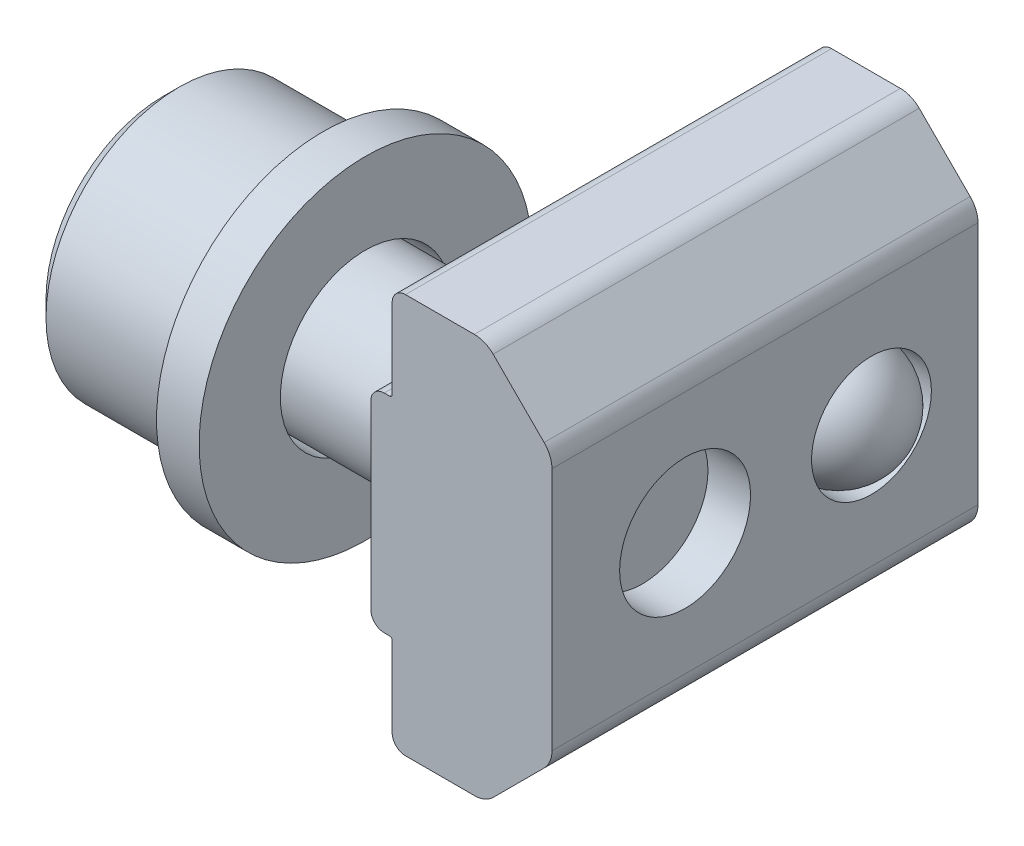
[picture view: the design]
ISO-10303-21;
HEADER;
FILE_DESCRIPTION(('STEP AP214'),'2;1');
FILE_NAME('part.step','',(''),(''),'','','');
FILE_SCHEMA(('AUTOMOTIVE_DESIGN { 1 0 10303 214 1 1 1 1 }'));
ENDSEC;
DATA;
#1=APPLICATION_CONTEXT('core data for automotive mechanical design processes');
#2=APPLICATION_PROTOCOL_DEFINITION('international standard','automotive_design',2000,#1);
#3=PRODUCT_CONTEXT('',#1,'mechanical');
#4=PRODUCT('Part','Part','',(#3));
#5=PRODUCT_RELATED_PRODUCT_CATEGORY('part','',(#4));
#6=PRODUCT_DEFINITION_FORMATION('','',#4);
#7=PRODUCT_DEFINITION_CONTEXT('part definition',#1,'design');
#8=PRODUCT_DEFINITION('design','',#6,#7);
#9=PRODUCT_DEFINITION_SHAPE('','',#8);
#10=(LENGTH_UNIT() NAMED_UNIT(*) SI_UNIT(.MILLI.,.METRE.));
#11=(NAMED_UNIT(*) PLANE_ANGLE_UNIT() SI_UNIT($,.RADIAN.));
#12=(NAMED_UNIT(*) SI_UNIT($,.STERADIAN.) SOLID_ANGLE_UNIT());
#13=UNCERTAINTY_MEASURE_WITH_UNIT(LENGTH_MEASURE(1.E-05),#10,'distance_accuracy_value','');
#14=(GEOMETRIC_REPRESENTATION_CONTEXT(3) GLOBAL_UNCERTAINTY_ASSIGNED_CONTEXT((#13)) GLOBAL_UNIT_ASSIGNED_CONTEXT((#10,
#11,#12)) REPRESENTATION_CONTEXT('',''));
#15=CARTESIAN_POINT('',(0.,0.,0.));
#16=DIRECTION('',(0.,0.,1.));
#17=DIRECTION('',(1.,0.,0.));
#18=AXIS2_PLACEMENT_3D('',#15,#16,#17);
#19=CARTESIAN_POINT('',(11.,4.5857864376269,-11.));
#20=DIRECTION('',(0.,0.,1.));
#21=DIRECTION('',(1.,0.,0.));
#22=AXIS2_PLACEMENT_3D('',#19,#20,#21);
#23=CYLINDRICAL_SURFACE('',#22,0.999999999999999);
#24=CARTESIAN_POINT('',(11.,4.5857864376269,5.));
#25=DIRECTION('',(0.,0.,1.));
#26=DIRECTION('',(1.,0.,0.));
#27=AXIS2_PLACEMENT_3D('',#24,#25,#26);
#28=CIRCLE('',#27,0.999999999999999);
#29=CARTESIAN_POINT('',(12.,4.5857864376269,5.));
#30=VERTEX_POINT('',#29);
#31=CARTESIAN_POINT('',(11.7071067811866,5.29289321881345,5.));
#32=VERTEX_POINT('',#31);
#33=EDGE_CURVE('E215',#30,#32,#28,.T.);
#34=ORIENTED_EDGE('',*,*,#33,.F.);
#35=DIRECTION('',(0.,0.,1.));
#36=VECTOR('',#35,1.);
#37=CARTESIAN_POINT('',(12.,4.5857864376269,-11.));
#38=LINE('',#37,#36);
#39=CARTESIAN_POINT('',(12.,4.5857864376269,-11.));
#40=VERTEX_POINT('',#39);
#41=EDGE_CURVE('E12',#40,#30,#38,.T.);
#42=ORIENTED_EDGE('',*,*,#41,.F.);
#43=CARTESIAN_POINT('',(11.,4.5857864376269,-11.));
#44=DIRECTION('',(0.,0.,1.));
#45=DIRECTION('',(1.,0.,0.));
#46=AXIS2_PLACEMENT_3D('',#43,#44,#45);
#47=CIRCLE('',#46,0.999999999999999);
#48=CARTESIAN_POINT('',(11.7071067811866,5.29289321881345,-11.));
#49=VERTEX_POINT('',#48);
#50=EDGE_CURVE('E272',#40,#49,#47,.T.);
#51=ORIENTED_EDGE('',*,*,#50,.T.);
#52=DIRECTION('',(0.,0.,1.));
#53=VECTOR('',#52,1.);
#54=CARTESIAN_POINT('',(11.7071067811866,5.29289321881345,-11.));
#55=LINE('',#54,#53);
#56=EDGE_CURVE('E137',#49,#32,#55,.T.);
#57=ORIENTED_EDGE('',*,*,#56,.T.);
#58=EDGE_LOOP('',(#34,#42,#51,#57));
#59=FACE_BOUND('',#58,.T.);
#60=ADVANCED_FACE('F45',(#59),#23,.T.);
#61=CARTESIAN_POINT('',(12.,-4.5857864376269,-11.));
#62=DIRECTION('',(1.,0.,0.));
#63=DIRECTION('',(0.,0.,-1.));
#64=AXIS2_PLACEMENT_3D('',#61,#62,#63);
#65=PLANE('',#64);
#66=CARTESIAN_POINT('',(12.,0.,0.));
#67=DIRECTION('',(1.,0.,0.));
#68=DIRECTION('',(0.,0.,-1.));
#69=AXIS2_PLACEMENT_3D('',#66,#67,#68);
#70=CIRCLE('',#69,2.4585);
#71=CARTESIAN_POINT('',(12.,0.,-2.4585));
#72=VERTEX_POINT('',#71);
#73=EDGE_CURVE('E48',#72,#72,#70,.T.);
#74=ORIENTED_EDGE('',*,*,#73,.F.);
#75=EDGE_LOOP('',(#74));
#76=FACE_BOUND('',#75,.T.);
#77=CARTESIAN_POINT('',(12.,0.,-7.));
#78=DIRECTION('',(1.,0.,0.));
#79=DIRECTION('',(0.,0.,-1.));
#80=AXIS2_PLACEMENT_3D('',#77,#78,#79);
#81=CIRCLE('',#80,2.25);
#82=CARTESIAN_POINT('',(12.,0.,-9.25));
#83=VERTEX_POINT('',#82);
#84=EDGE_CURVE('E219',#83,#83,#81,.T.);
#85=ORIENTED_EDGE('',*,*,#84,.F.);
#86=EDGE_LOOP('',(#85));
#87=FACE_BOUND('',#86,.T.);
#88=DIRECTION('',(0.,1.,0.));
#89=VECTOR('',#88,1.);
#90=CARTESIAN_POINT('',(12.,-4.5857864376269,5.));
#91=LINE('',#90,#89);
#92=CARTESIAN_POINT('',(12.,-4.5857864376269,5.));
#93=VERTEX_POINT('',#92);
#94=EDGE_CURVE('E270',#93,#30,#91,.T.);
#95=ORIENTED_EDGE('',*,*,#94,.F.);
#96=DIRECTION('',(0.,0.,1.));
#97=VECTOR('',#96,1.);
#98=CARTESIAN_POINT('',(12.,-4.5857864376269,-11.));
#99=LINE('',#98,#97);
#100=CARTESIAN_POINT('',(12.,-4.5857864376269,-11.));
#101=VERTEX_POINT('',#100);
#102=EDGE_CURVE('E54',#101,#93,#99,.T.);
#103=ORIENTED_EDGE('',*,*,#102,.F.);
#104=DIRECTION('',(0.,1.,0.));
#105=VECTOR('',#104,1.);
#106=CARTESIAN_POINT('',(12.,-4.5857864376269,-11.));
#107=LINE('',#106,#105);
#108=EDGE_CURVE('E205',#101,#40,#107,.T.);
#109=ORIENTED_EDGE('',*,*,#108,.T.);
#110=ORIENTED_EDGE('',*,*,#41,.T.);
#111=EDGE_LOOP('',(#95,#103,#109,#110));
#112=FACE_BOUND('',#111,.T.);
#113=ADVANCED_FACE('F309',(#76,#87,#112),#65,.T.);
#114=CARTESIAN_POINT('',(11.,-4.5857864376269,-11.));
#115=DIRECTION('',(0.,0.,1.));
#116=DIRECTION('',(1.,0.,0.));
#117=AXIS2_PLACEMENT_3D('',#114,#115,#116);
#118=CYLINDRICAL_SURFACE('',#117,0.999999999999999);
#119=CARTESIAN_POINT('',(11.,-4.5857864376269,5.));
#120=DIRECTION('',(0.,0.,1.));
#121=DIRECTION('',(1.,0.,0.));
#122=AXIS2_PLACEMENT_3D('',#119,#120,#121);
#123=CIRCLE('',#122,0.999999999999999);
#124=CARTESIAN_POINT('',(11.7071067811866,-5.29289321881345,5.));
#125=VERTEX_POINT('',#124);
#126=EDGE_CURVE('E192',#125,#93,#123,.T.);
#127=ORIENTED_EDGE('',*,*,#126,.F.);
#128=DIRECTION('',(0.,0.,1.));
#129=VECTOR('',#128,1.);
#130=CARTESIAN_POINT('',(11.7071067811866,-5.29289321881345,-11.));
#131=LINE('',#130,#129);
#132=CARTESIAN_POINT('',(11.7071067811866,-5.29289321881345,-11.));
#133=VERTEX_POINT('',#132);
#134=EDGE_CURVE('E187',#133,#125,#131,.T.);
#135=ORIENTED_EDGE('',*,*,#134,.F.);
#136=CARTESIAN_POINT('',(11.,-4.5857864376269,-11.));
#137=DIRECTION('',(0.,0.,1.));
#138=DIRECTION('',(1.,0.,0.));
#139=AXIS2_PLACEMENT_3D('',#136,#137,#138);
#140=CIRCLE('',#139,0.999999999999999);
#141=EDGE_CURVE('E190',#133,#101,#140,.T.);
#142=ORIENTED_EDGE('',*,*,#141,.T.);
#143=ORIENTED_EDGE('',*,*,#102,.T.);
#144=EDGE_LOOP('',(#127,#135,#142,#143));
#145=FACE_BOUND('',#144,.T.);
#146=ADVANCED_FACE('F189',(#145),#118,.T.);
#147=CARTESIAN_POINT('',(9.79289321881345,-7.20710678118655,-11.));
#148=DIRECTION('',(0.707106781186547,-0.707106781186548,0.));
#149=DIRECTION('',(0.707106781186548,0.707106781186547,0.));
#150=AXIS2_PLACEMENT_3D('',#147,#148,#149);
#151=PLANE('',#150);
#152=DIRECTION('',(0.707106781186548,0.707106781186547,0.));
#153=VECTOR('',#152,1.);
#154=CARTESIAN_POINT('',(9.79289321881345,-7.20710678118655,5.));
#155=LINE('',#154,#153);
#156=CARTESIAN_POINT('',(9.79289321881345,-7.20710678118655,5.));
#157=VERTEX_POINT('',#156);
#158=EDGE_CURVE('E267',#157,#125,#155,.T.);
#159=ORIENTED_EDGE('',*,*,#158,.F.);
#160=DIRECTION('',(0.,0.,1.));
#161=VECTOR('',#160,1.);
#162=CARTESIAN_POINT('',(9.79289321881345,-7.20710678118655,-11.));
#163=LINE('',#162,#161);
#164=CARTESIAN_POINT('',(9.79289321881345,-7.20710678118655,-11.));
#165=VERTEX_POINT('',#164);
#166=EDGE_CURVE('E197',#165,#157,#163,.T.);
#167=ORIENTED_EDGE('',*,*,#166,.F.);
#168=DIRECTION('',(0.707106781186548,0.707106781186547,0.));
#169=VECTOR('',#168,1.);
#170=CARTESIAN_POINT('',(9.79289321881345,-7.20710678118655,-11.));
#171=LINE('',#170,#169);
#172=EDGE_CURVE('E203',#165,#133,#171,.T.);
#173=ORIENTED_EDGE('',*,*,#172,.T.);
#174=ORIENTED_EDGE('',*,*,#134,.T.);
#175=EDGE_LOOP('',(#159,#167,#173,#174));
#176=FACE_BOUND('',#175,.T.);
#177=ADVANCED_FACE('F207',(#176),#151,.T.);
#178=CARTESIAN_POINT('',(9.08578643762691,-6.5,-11.));
#179=DIRECTION('',(0.,0.,1.));
#180=DIRECTION('',(1.,0.,0.));
#181=AXIS2_PLACEMENT_3D('',#178,#179,#180);
#182=CYLINDRICAL_SURFACE('',#181,1.);
#183=CARTESIAN_POINT('',(9.08578643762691,-6.5,5.));
#184=DIRECTION('',(0.,0.,1.));
#185=DIRECTION('',(1.,0.,0.));
#186=AXIS2_PLACEMENT_3D('',#183,#184,#185);
#187=CIRCLE('',#186,1.);
#188=CARTESIAN_POINT('',(9.08578643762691,-7.5,5.));
#189=VERTEX_POINT('',#188);
#190=EDGE_CURVE('E264',#189,#157,#187,.T.);
#191=ORIENTED_EDGE('',*,*,#190,.F.);
#192=DIRECTION('',(0.,0.,1.));
#193=VECTOR('',#192,1.);
#194=CARTESIAN_POINT('',(9.08578643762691,-7.5,-11.));
#195=LINE('',#194,#193);
#196=CARTESIAN_POINT('',(9.08578643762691,-7.5,-11.));
#197=VERTEX_POINT('',#196);
#198=EDGE_CURVE('E276',#197,#189,#195,.T.);
#199=ORIENTED_EDGE('',*,*,#198,.F.);
#200=CARTESIAN_POINT('',(9.08578643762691,-6.5,-11.));
#201=DIRECTION('',(0.,0.,1.));
#202=DIRECTION('',(1.,0.,0.));
#203=AXIS2_PLACEMENT_3D('',#200,#201,#202);
#204=CIRCLE('',#203,1.);
#205=EDGE_CURVE('E208',#197,#165,#204,.T.);
#206=ORIENTED_EDGE('',*,*,#205,.T.);
#207=ORIENTED_EDGE('',*,*,#166,.T.);
#208=EDGE_LOOP('',(#191,#199,#206,#207));
#209=FACE_BOUND('',#208,.T.);
#210=ADVANCED_FACE('F325',(#209),#182,.T.);
#211=CARTESIAN_POINT('',(6.49999999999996,-7.5,-11.));
#212=DIRECTION('',(0.,-1.,0.));
#213=DIRECTION('',(0.,0.,-1.));
#214=AXIS2_PLACEMENT_3D('',#211,#212,#213);
#215=PLANE('',#214);
#216=DIRECTION('',(1.,0.,0.));
#217=VECTOR('',#216,1.);
#218=CARTESIAN_POINT('',(6.49999999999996,-7.5,5.));
#219=LINE('',#218,#217);
#220=CARTESIAN_POINT('',(6.49999999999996,-7.5,5.));
#221=VERTEX_POINT('',#220);
#222=EDGE_CURVE('E261',#221,#189,#219,.T.);
#223=ORIENTED_EDGE('',*,*,#222,.F.);
#224=DIRECTION('',(0.,0.,1.));
#225=VECTOR('',#224,1.);
#226=CARTESIAN_POINT('',(6.49999999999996,-7.5,-11.));
#227=LINE('',#226,#225);
#228=CARTESIAN_POINT('',(6.49999999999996,-7.5,-11.));
#229=VERTEX_POINT('',#228);
#230=EDGE_CURVE('E278',#229,#221,#227,.T.);
#231=ORIENTED_EDGE('',*,*,#230,.F.);
#232=DIRECTION('',(1.,0.,0.));
#233=VECTOR('',#232,1.);
#234=CARTESIAN_POINT('',(6.49999999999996,-7.5,-11.));
#235=LINE('',#234,#233);
#236=EDGE_CURVE('E210',#229,#197,#235,.T.);
#237=ORIENTED_EDGE('',*,*,#236,.T.);
#238=ORIENTED_EDGE('',*,*,#198,.T.);
#239=EDGE_LOOP('',(#223,#231,#237,#238));
#240=FACE_BOUND('',#239,.T.);
#241=ADVANCED_FACE('F328',(#240),#215,.T.);
#242=CARTESIAN_POINT('',(6.49999999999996,-7.00000000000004,-11.));
#243=DIRECTION('',(0.,0.,1.));
#244=DIRECTION('',(1.,0.,0.));
#245=AXIS2_PLACEMENT_3D('',#242,#243,#244);
#246=CYLINDRICAL_SURFACE('',#245,0.499999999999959);
#247=CARTESIAN_POINT('',(6.49999999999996,-7.00000000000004,5.));
#248=DIRECTION('',(0.,0.,1.));
#249=DIRECTION('',(1.,0.,0.));
#250=AXIS2_PLACEMENT_3D('',#247,#248,#249);
#251=CIRCLE('',#250,0.499999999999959);
#252=CARTESIAN_POINT('',(6.,-7.00000000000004,5.));
#253=VERTEX_POINT('',#252);
#254=EDGE_CURVE('E258',#253,#221,#251,.T.);
#255=ORIENTED_EDGE('',*,*,#254,.F.);
#256=DIRECTION('',(0.,0.,1.));
#257=VECTOR('',#256,1.);
#258=CARTESIAN_POINT('',(6.,-7.00000000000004,-11.));
#259=LINE('',#258,#257);
#260=CARTESIAN_POINT('',(6.,-7.00000000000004,-11.));
#261=VERTEX_POINT('',#260);
#262=EDGE_CURVE('E280',#261,#253,#259,.T.);
#263=ORIENTED_EDGE('',*,*,#262,.F.);
#264=CARTESIAN_POINT('',(6.49999999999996,-7.00000000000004,-11.));
#265=DIRECTION('',(0.,0.,1.));
#266=DIRECTION('',(1.,0.,0.));
#267=AXIS2_PLACEMENT_3D('',#264,#265,#266);
#268=CIRCLE('',#267,0.499999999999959);
#269=EDGE_CURVE('E456',#261,#229,#268,.T.);
#270=ORIENTED_EDGE('',*,*,#269,.T.);
#271=ORIENTED_EDGE('',*,*,#230,.T.);
#272=EDGE_LOOP('',(#255,#263,#270,#271));
#273=FACE_BOUND('',#272,.T.);
#274=ADVANCED_FACE('F332',(#273),#246,.T.);
#275=CARTESIAN_POINT('',(6.,-3.99999999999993,-11.));
#276=DIRECTION('',(-1.,0.,0.));
#277=DIRECTION('',(0.,0.,1.));
#278=AXIS2_PLACEMENT_3D('',#275,#276,#277);
#279=PLANE('',#278);
#280=DIRECTION('',(0.,-1.,0.));
#281=VECTOR('',#280,1.);
#282=CARTESIAN_POINT('',(6.,-3.99999999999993,5.));
#283=LINE('',#282,#281);
#284=CARTESIAN_POINT('',(6.,-3.99999999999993,5.));
#285=VERTEX_POINT('',#284);
#286=EDGE_CURVE('E255',#285,#253,#283,.T.);
#287=ORIENTED_EDGE('',*,*,#286,.F.);
#288=DIRECTION('',(0.,0.,1.));
#289=VECTOR('',#288,1.);
#290=CARTESIAN_POINT('',(6.,-3.99999999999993,-11.));
#291=LINE('',#290,#289);
#292=CARTESIAN_POINT('',(6.,-3.99999999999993,-11.));
#293=VERTEX_POINT('',#292);
#294=EDGE_CURVE('E282',#293,#285,#291,.T.);
#295=ORIENTED_EDGE('',*,*,#294,.F.);
#296=DIRECTION('',(0.,-1.,0.));
#297=VECTOR('',#296,1.);
#298=CARTESIAN_POINT('',(6.,-3.99999999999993,-11.));
#299=LINE('',#298,#297);
#300=EDGE_CURVE('E453',#293,#261,#299,.T.);
#301=ORIENTED_EDGE('',*,*,#300,.T.);
#302=ORIENTED_EDGE('',*,*,#262,.T.);
#303=EDGE_LOOP('',(#287,#295,#301,#302));
#304=FACE_BOUND('',#303,.T.);
#305=ADVANCED_FACE('F336',(#304),#279,.T.);
#306=CARTESIAN_POINT('',(5.90000000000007,-3.99999999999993,-11.));
#307=DIRECTION('',(0.,0.,1.));
#308=DIRECTION('',(1.,0.,0.));
#309=AXIS2_PLACEMENT_3D('',#306,#307,#308);
#310=CYLINDRICAL_SURFACE('',#309,0.0999999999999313);
#311=CARTESIAN_POINT('',(5.90000000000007,-3.99999999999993,5.));
#312=DIRECTION('',(0.,0.,-1.));
#313=DIRECTION('',(1.,0.,0.));
#314=AXIS2_PLACEMENT_3D('',#311,#312,#313);
#315=CIRCLE('',#314,0.0999999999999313);
#316=CARTESIAN_POINT('',(5.90000000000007,-3.9,5.));
#317=VERTEX_POINT('',#316);
#318=EDGE_CURVE('E252',#317,#285,#315,.T.);
#319=ORIENTED_EDGE('',*,*,#318,.F.);
#320=DIRECTION('',(0.,0.,1.));
#321=VECTOR('',#320,1.);
#322=CARTESIAN_POINT('',(5.90000000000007,-3.9,-11.));
#323=LINE('',#322,#321);
#324=CARTESIAN_POINT('',(5.90000000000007,-3.9,-11.));
#325=VERTEX_POINT('',#324);
#326=EDGE_CURVE('E284',#325,#317,#323,.T.);
#327=ORIENTED_EDGE('',*,*,#326,.F.);
#328=CARTESIAN_POINT('',(5.90000000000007,-3.99999999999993,-11.));
#329=DIRECTION('',(0.,0.,-1.));
#330=DIRECTION('',(1.,0.,0.));
#331=AXIS2_PLACEMENT_3D('',#328,#329,#330);
#332=CIRCLE('',#331,0.0999999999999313);
#333=EDGE_CURVE('E450',#325,#293,#332,.T.);
#334=ORIENTED_EDGE('',*,*,#333,.T.);
#335=ORIENTED_EDGE('',*,*,#294,.T.);
#336=EDGE_LOOP('',(#319,#327,#334,#335));
#337=FACE_BOUND('',#336,.T.);
#338=ADVANCED_FACE('F340',(#337),#310,.F.);
#339=CARTESIAN_POINT('',(5.69999999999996,-3.9,-11.));
#340=DIRECTION('',(0.,-1.,0.));
#341=DIRECTION('',(1.,0.,0.));
#342=AXIS2_PLACEMENT_3D('',#339,#340,#341);
#343=PLANE('',#342);
#344=DIRECTION('',(1.,0.,0.));
#345=VECTOR('',#344,1.);
#346=CARTESIAN_POINT('',(5.69999999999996,-3.9,5.));
#347=LINE('',#346,#345);
#348=CARTESIAN_POINT('',(5.69999999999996,-3.9,5.));
#349=VERTEX_POINT('',#348);
#350=EDGE_CURVE('E249',#349,#317,#347,.T.);
#351=ORIENTED_EDGE('',*,*,#350,.F.);
#352=DIRECTION('',(0.,0.,1.));
#353=VECTOR('',#352,1.);
#354=CARTESIAN_POINT('',(5.69999999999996,-3.9,-11.));
#355=LINE('',#354,#353);
#356=CARTESIAN_POINT('',(5.69999999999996,-3.9,-11.));
#357=VERTEX_POINT('',#356);
#358=EDGE_CURVE('E286',#357,#349,#355,.T.);
#359=ORIENTED_EDGE('',*,*,#358,.F.);
#360=DIRECTION('',(1.,0.,0.));
#361=VECTOR('',#360,1.);
#362=CARTESIAN_POINT('',(5.69999999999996,-3.9,-11.));
#363=LINE('',#362,#361);
#364=EDGE_CURVE('E447',#357,#325,#363,.T.);
#365=ORIENTED_EDGE('',*,*,#364,.T.);
#366=ORIENTED_EDGE('',*,*,#326,.T.);
#367=EDGE_LOOP('',(#351,#359,#365,#366));
#368=FACE_BOUND('',#367,.T.);
#369=ADVANCED_FACE('F344',(#368),#343,.T.);
#370=CARTESIAN_POINT('',(5.69999999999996,-3.40000000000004,-11.));
#371=DIRECTION('',(0.,0.,1.));
#372=DIRECTION('',(1.,0.,0.));
#373=AXIS2_PLACEMENT_3D('',#370,#371,#372);
#374=CYLINDRICAL_SURFACE('',#373,0.499999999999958);
#375=CARTESIAN_POINT('',(5.69999999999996,-3.40000000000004,5.));
#376=DIRECTION('',(0.,0.,1.));
#377=DIRECTION('',(1.,0.,0.));
#378=AXIS2_PLACEMENT_3D('',#375,#376,#377);
#379=CIRCLE('',#378,0.499999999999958);
#380=CARTESIAN_POINT('',(5.2,-3.40000000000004,5.));
#381=VERTEX_POINT('',#380);
#382=EDGE_CURVE('E246',#381,#349,#379,.T.);
#383=ORIENTED_EDGE('',*,*,#382,.F.);
#384=DIRECTION('',(0.,0.,1.));
#385=VECTOR('',#384,1.);
#386=CARTESIAN_POINT('',(5.2,-3.40000000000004,-11.));
#387=LINE('',#386,#385);
#388=CARTESIAN_POINT('',(5.2,-3.40000000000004,-11.));
#389=VERTEX_POINT('',#388);
#390=EDGE_CURVE('E288',#389,#381,#387,.T.);
#391=ORIENTED_EDGE('',*,*,#390,.F.);
#392=CARTESIAN_POINT('',(5.69999999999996,-3.40000000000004,-11.));
#393=DIRECTION('',(0.,0.,1.));
#394=DIRECTION('',(1.,0.,0.));
#395=AXIS2_PLACEMENT_3D('',#392,#393,#394);
#396=CIRCLE('',#395,0.499999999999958);
#397=EDGE_CURVE('E444',#389,#357,#396,.T.);
#398=ORIENTED_EDGE('',*,*,#397,.T.);
#399=ORIENTED_EDGE('',*,*,#358,.T.);
#400=EDGE_LOOP('',(#383,#391,#398,#399));
#401=FACE_BOUND('',#400,.T.);
#402=ADVANCED_FACE('F348',(#401),#374,.T.);
#403=CARTESIAN_POINT('',(5.2,3.40000000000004,-11.));
#404=DIRECTION('',(-1.,0.,0.));
#405=DIRECTION('',(0.,0.,1.));
#406=AXIS2_PLACEMENT_3D('',#403,#404,#405);
#407=PLANE('',#406);
#408=CARTESIAN_POINT('',(5.2,0.,0.));
#409=DIRECTION('',(-1.,0.,0.));
#410=DIRECTION('',(0.,0.,1.));
#411=AXIS2_PLACEMENT_3D('',#408,#409,#410);
#412=CIRCLE('',#411,2.4585);
#413=CARTESIAN_POINT('',(5.2,0.,2.4585));
#414=VERTEX_POINT('',#413);
#415=EDGE_CURVE('E409',#414,#414,#412,.T.);
#416=ORIENTED_EDGE('',*,*,#415,.F.);
#417=EDGE_LOOP('',(#416));
#418=FACE_BOUND('',#417,.T.);
#419=DIRECTION('',(0.,-1.,0.));
#420=VECTOR('',#419,1.);
#421=CARTESIAN_POINT('',(5.2,3.40000000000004,5.));
#422=LINE('',#421,#420);
#423=CARTESIAN_POINT('',(5.2,3.40000000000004,5.));
#424=VERTEX_POINT('',#423);
#425=EDGE_CURVE('E243',#424,#381,#422,.T.);
#426=ORIENTED_EDGE('',*,*,#425,.F.);
#427=DIRECTION('',(0.,0.,1.));
#428=VECTOR('',#427,1.);
#429=CARTESIAN_POINT('',(5.2,3.40000000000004,-11.));
#430=LINE('',#429,#428);
#431=CARTESIAN_POINT('',(5.2,3.40000000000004,-11.));
#432=VERTEX_POINT('',#431);
#433=EDGE_CURVE('E290',#432,#424,#430,.T.);
#434=ORIENTED_EDGE('',*,*,#433,.F.);
#435=DIRECTION('',(0.,-1.,0.));
#436=VECTOR('',#435,1.);
#437=CARTESIAN_POINT('',(5.2,3.40000000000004,-11.));
#438=LINE('',#437,#436);
#439=EDGE_CURVE('E441',#432,#389,#438,.T.);
#440=ORIENTED_EDGE('',*,*,#439,.T.);
#441=ORIENTED_EDGE('',*,*,#390,.T.);
#442=EDGE_LOOP('',(#426,#434,#440,#441));
#443=FACE_BOUND('',#442,.T.);
#444=ADVANCED_FACE('F352',(#418,#443),#407,.T.);
#445=CARTESIAN_POINT('',(5.69999999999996,3.40000000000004,-11.));
#446=DIRECTION('',(0.,0.,1.));
#447=DIRECTION('',(1.,0.,0.));
#448=AXIS2_PLACEMENT_3D('',#445,#446,#447);
#449=CYLINDRICAL_SURFACE('',#448,0.49999999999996);
#450=CARTESIAN_POINT('',(5.69999999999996,3.40000000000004,5.));
#451=DIRECTION('',(0.,0.,1.));
#452=DIRECTION('',(1.,0.,0.));
#453=AXIS2_PLACEMENT_3D('',#450,#451,#452);
#454=CIRCLE('',#453,0.49999999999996);
#455=CARTESIAN_POINT('',(5.69999999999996,3.9,5.));
#456=VERTEX_POINT('',#455);
#457=EDGE_CURVE('E240',#456,#424,#454,.T.);
#458=ORIENTED_EDGE('',*,*,#457,.F.);
#459=DIRECTION('',(0.,0.,1.));
#460=VECTOR('',#459,1.);
#461=CARTESIAN_POINT('',(5.69999999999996,3.9,-11.));
#462=LINE('',#461,#460);
#463=CARTESIAN_POINT('',(5.69999999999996,3.9,-11.));
#464=VERTEX_POINT('',#463);
#465=EDGE_CURVE('E292',#464,#456,#462,.T.);
#466=ORIENTED_EDGE('',*,*,#465,.F.);
#467=CARTESIAN_POINT('',(5.69999999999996,3.40000000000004,-11.));
#468=DIRECTION('',(0.,0.,1.));
#469=DIRECTION('',(1.,0.,0.));
#470=AXIS2_PLACEMENT_3D('',#467,#468,#469);
#471=CIRCLE('',#470,0.49999999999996);
#472=EDGE_CURVE('E438',#464,#432,#471,.T.);
#473=ORIENTED_EDGE('',*,*,#472,.T.);
#474=ORIENTED_EDGE('',*,*,#433,.T.);
#475=EDGE_LOOP('',(#458,#466,#473,#474));
#476=FACE_BOUND('',#475,.T.);
#477=ADVANCED_FACE('F356',(#476),#449,.T.);
#478=CARTESIAN_POINT('',(5.90000000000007,3.9,-11.));
#479=DIRECTION('',(0.,1.,0.));
#480=DIRECTION('',(0.,0.,1.));
#481=AXIS2_PLACEMENT_3D('',#478,#479,#480);
#482=PLANE('',#481);
#483=DIRECTION('',(-1.,0.,0.));
#484=VECTOR('',#483,1.);
#485=CARTESIAN_POINT('',(5.90000000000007,3.9,5.));
#486=LINE('',#485,#484);
#487=CARTESIAN_POINT('',(5.90000000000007,3.9,5.));
#488=VERTEX_POINT('',#487);
#489=EDGE_CURVE('E237',#488,#456,#486,.T.);
#490=ORIENTED_EDGE('',*,*,#489,.F.);
#491=DIRECTION('',(0.,0.,1.));
#492=VECTOR('',#491,1.);
#493=CARTESIAN_POINT('',(5.90000000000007,3.9,-11.));
#494=LINE('',#493,#492);
#495=CARTESIAN_POINT('',(5.90000000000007,3.9,-11.));
#496=VERTEX_POINT('',#495);
#497=EDGE_CURVE('E294',#496,#488,#494,.T.);
#498=ORIENTED_EDGE('',*,*,#497,.F.);
#499=DIRECTION('',(-1.,0.,0.));
#500=VECTOR('',#499,1.);
#501=CARTESIAN_POINT('',(5.90000000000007,3.9,-11.));
#502=LINE('',#501,#500);
#503=EDGE_CURVE('E435',#496,#464,#502,.T.);
#504=ORIENTED_EDGE('',*,*,#503,.T.);
#505=ORIENTED_EDGE('',*,*,#465,.T.);
#506=EDGE_LOOP('',(#490,#498,#504,#505));
#507=FACE_BOUND('',#506,.T.);
#508=ADVANCED_FACE('F360',(#507),#482,.T.);
#509=CARTESIAN_POINT('',(5.90000000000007,3.99999999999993,-11.));
#510=DIRECTION('',(0.,0.,1.));
#511=DIRECTION('',(1.,0.,0.));
#512=AXIS2_PLACEMENT_3D('',#509,#510,#511);
#513=CYLINDRICAL_SURFACE('',#512,0.0999999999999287);
#514=CARTESIAN_POINT('',(5.90000000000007,3.99999999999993,5.));
#515=DIRECTION('',(0.,0.,-1.));
#516=DIRECTION('',(1.,0.,0.));
#517=AXIS2_PLACEMENT_3D('',#514,#515,#516);
#518=CIRCLE('',#517,0.0999999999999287);
#519=CARTESIAN_POINT('',(6.,3.99999999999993,5.));
#520=VERTEX_POINT('',#519);
#521=EDGE_CURVE('E234',#520,#488,#518,.T.);
#522=ORIENTED_EDGE('',*,*,#521,.F.);
#523=DIRECTION('',(0.,0.,1.));
#524=VECTOR('',#523,1.);
#525=CARTESIAN_POINT('',(6.,3.99999999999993,-11.));
#526=LINE('',#525,#524);
#527=CARTESIAN_POINT('',(6.,3.99999999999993,-11.));
#528=VERTEX_POINT('',#527);
#529=EDGE_CURVE('E296',#528,#520,#526,.T.);
#530=ORIENTED_EDGE('',*,*,#529,.F.);
#531=CARTESIAN_POINT('',(5.90000000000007,3.99999999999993,-11.));
#532=DIRECTION('',(0.,0.,-1.));
#533=DIRECTION('',(1.,0.,0.));
#534=AXIS2_PLACEMENT_3D('',#531,#532,#533);
#535=CIRCLE('',#534,0.0999999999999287);
#536=EDGE_CURVE('E432',#528,#496,#535,.T.);
#537=ORIENTED_EDGE('',*,*,#536,.T.);
#538=ORIENTED_EDGE('',*,*,#497,.T.);
#539=EDGE_LOOP('',(#522,#530,#537,#538));
#540=FACE_BOUND('',#539,.T.);
#541=ADVANCED_FACE('F364',(#540),#513,.F.);
#542=CARTESIAN_POINT('',(6.,7.00000000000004,-11.));
#543=DIRECTION('',(-1.,0.,0.));
#544=DIRECTION('',(0.,0.,1.));
#545=AXIS2_PLACEMENT_3D('',#542,#543,#544);
#546=PLANE('',#545);
#547=DIRECTION('',(0.,-1.,0.));
#548=VECTOR('',#547,1.);
#549=CARTESIAN_POINT('',(6.,7.00000000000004,5.));
#550=LINE('',#549,#548);
#551=CARTESIAN_POINT('',(6.,7.00000000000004,5.));
#552=VERTEX_POINT('',#551);
#553=EDGE_CURVE('E231',#552,#520,#550,.T.);
#554=ORIENTED_EDGE('',*,*,#553,.F.);
#555=DIRECTION('',(0.,0.,1.));
#556=VECTOR('',#555,1.);
#557=CARTESIAN_POINT('',(6.,7.00000000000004,-11.));
#558=LINE('',#557,#556);
#559=CARTESIAN_POINT('',(6.,7.00000000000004,-11.));
#560=VERTEX_POINT('',#559);
#561=EDGE_CURVE('E298',#560,#552,#558,.T.);
#562=ORIENTED_EDGE('',*,*,#561,.F.);
#563=DIRECTION('',(0.,-1.,0.));
#564=VECTOR('',#563,1.);
#565=CARTESIAN_POINT('',(6.,7.00000000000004,-11.));
#566=LINE('',#565,#564);
#567=EDGE_CURVE('E429',#560,#528,#566,.T.);
#568=ORIENTED_EDGE('',*,*,#567,.T.);
#569=ORIENTED_EDGE('',*,*,#529,.T.);
#570=EDGE_LOOP('',(#554,#562,#568,#569));
#571=FACE_BOUND('',#570,.T.);
#572=ADVANCED_FACE('F368',(#571),#546,.T.);
#573=CARTESIAN_POINT('',(6.49999999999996,7.00000000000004,-11.));
#574=DIRECTION('',(0.,0.,1.));
#575=DIRECTION('',(1.,0.,0.));
#576=AXIS2_PLACEMENT_3D('',#573,#574,#575);
#577=CYLINDRICAL_SURFACE('',#576,0.499999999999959);
#578=CARTESIAN_POINT('',(6.49999999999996,7.00000000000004,5.));
#579=DIRECTION('',(0.,0.,1.));
#580=DIRECTION('',(1.,0.,0.));
#581=AXIS2_PLACEMENT_3D('',#578,#579,#580);
#582=CIRCLE('',#581,0.499999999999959);
#583=CARTESIAN_POINT('',(6.49999999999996,7.5,5.));
#584=VERTEX_POINT('',#583);
#585=EDGE_CURVE('E228',#584,#552,#582,.T.);
#586=ORIENTED_EDGE('',*,*,#585,.F.);
#587=DIRECTION('',(0.,0.,1.));
#588=VECTOR('',#587,1.);
#589=CARTESIAN_POINT('',(6.49999999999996,7.5,-11.));
#590=LINE('',#589,#588);
#591=CARTESIAN_POINT('',(6.49999999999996,7.5,-11.));
#592=VERTEX_POINT('',#591);
#593=EDGE_CURVE('E300',#592,#584,#590,.T.);
#594=ORIENTED_EDGE('',*,*,#593,.F.);
#595=CARTESIAN_POINT('',(6.49999999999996,7.00000000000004,-11.));
#596=DIRECTION('',(0.,0.,1.));
#597=DIRECTION('',(1.,0.,0.));
#598=AXIS2_PLACEMENT_3D('',#595,#596,#597);
#599=CIRCLE('',#598,0.499999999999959);
#600=EDGE_CURVE('E426',#592,#560,#599,.T.);
#601=ORIENTED_EDGE('',*,*,#600,.T.);
#602=ORIENTED_EDGE('',*,*,#561,.T.);
#603=EDGE_LOOP('',(#586,#594,#601,#602));
#604=FACE_BOUND('',#603,.T.);
#605=ADVANCED_FACE('F372',(#604),#577,.T.);
#606=CARTESIAN_POINT('',(9.08578643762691,7.5,-11.));
#607=DIRECTION('',(0.,1.,0.));
#608=DIRECTION('',(0.,0.,1.));
#609=AXIS2_PLACEMENT_3D('',#606,#607,#608);
#610=PLANE('',#609);
#611=DIRECTION('',(-1.,0.,0.));
#612=VECTOR('',#611,1.);
#613=CARTESIAN_POINT('',(9.08578643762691,7.5,5.));
#614=LINE('',#613,#612);
#615=CARTESIAN_POINT('',(9.08578643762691,7.5,5.));
#616=VERTEX_POINT('',#615);
#617=EDGE_CURVE('E225',#616,#584,#614,.T.);
#618=ORIENTED_EDGE('',*,*,#617,.F.);
#619=DIRECTION('',(0.,0.,1.));
#620=VECTOR('',#619,1.);
#621=CARTESIAN_POINT('',(9.08578643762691,7.5,-11.));
#622=LINE('',#621,#620);
#623=CARTESIAN_POINT('',(9.08578643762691,7.5,-11.));
#624=VERTEX_POINT('',#623);
#625=EDGE_CURVE('E302',#624,#616,#622,.T.);
#626=ORIENTED_EDGE('',*,*,#625,.F.);
#627=DIRECTION('',(-1.,0.,0.));
#628=VECTOR('',#627,1.);
#629=CARTESIAN_POINT('',(9.08578643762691,7.5,-11.));
#630=LINE('',#629,#628);
#631=EDGE_CURVE('E423',#624,#592,#630,.T.);
#632=ORIENTED_EDGE('',*,*,#631,.T.);
#633=ORIENTED_EDGE('',*,*,#593,.T.);
#634=EDGE_LOOP('',(#618,#626,#632,#633));
#635=FACE_BOUND('',#634,.T.);
#636=ADVANCED_FACE('F376',(#635),#610,.T.);
#637=CARTESIAN_POINT('',(9.08578643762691,6.5,-11.));
#638=DIRECTION('',(0.,0.,1.));
#639=DIRECTION('',(1.,0.,0.));
#640=AXIS2_PLACEMENT_3D('',#637,#638,#639);
#641=CYLINDRICAL_SURFACE('',#640,1.);
#642=CARTESIAN_POINT('',(9.08578643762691,6.5,5.));
#643=DIRECTION('',(0.,0.,1.));
#644=DIRECTION('',(1.,0.,0.));
#645=AXIS2_PLACEMENT_3D('',#642,#643,#644);
#646=CIRCLE('',#645,1.);
#647=CARTESIAN_POINT('',(9.79289321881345,7.20710678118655,5.));
#648=VERTEX_POINT('',#647);
#649=EDGE_CURVE('E222',#648,#616,#646,.T.);
#650=ORIENTED_EDGE('',*,*,#649,.F.);
#651=DIRECTION('',(0.,0.,1.));
#652=VECTOR('',#651,1.);
#653=CARTESIAN_POINT('',(9.79289321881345,7.20710678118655,-11.));
#654=LINE('',#653,#652);
#655=CARTESIAN_POINT('',(9.79289321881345,7.20710678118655,-11.));
#656=VERTEX_POINT('',#655);
#657=EDGE_CURVE('E304',#656,#648,#654,.T.);
#658=ORIENTED_EDGE('',*,*,#657,.F.);
#659=CARTESIAN_POINT('',(9.08578643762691,6.5,-11.));
#660=DIRECTION('',(0.,0.,1.));
#661=DIRECTION('',(1.,0.,0.));
#662=AXIS2_PLACEMENT_3D('',#659,#660,#661);
#663=CIRCLE('',#662,1.);
#664=EDGE_CURVE('E420',#656,#624,#663,.T.);
#665=ORIENTED_EDGE('',*,*,#664,.T.);
#666=ORIENTED_EDGE('',*,*,#625,.T.);
#667=EDGE_LOOP('',(#650,#658,#665,#666));
#668=FACE_BOUND('',#667,.T.);
#669=ADVANCED_FACE('F380',(#668),#641,.T.);
#670=CARTESIAN_POINT('',(11.7071067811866,5.29289321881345,-11.));
#671=DIRECTION('',(0.707106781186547,0.707106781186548,0.));
#672=DIRECTION('',(-0.707106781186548,0.707106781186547,0.));
#673=AXIS2_PLACEMENT_3D('',#670,#671,#672);
#674=PLANE('',#673);
#675=DIRECTION('',(-0.707106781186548,0.707106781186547,0.));
#676=VECTOR('',#675,1.);
#677=CARTESIAN_POINT('',(11.7071067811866,5.29289321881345,5.));
#678=LINE('',#677,#676);
#679=EDGE_CURVE('E218',#32,#648,#678,.T.);
#680=ORIENTED_EDGE('',*,*,#679,.F.);
#681=ORIENTED_EDGE('',*,*,#56,.F.);
#682=DIRECTION('',(-0.707106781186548,0.707106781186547,0.));
#683=VECTOR('',#682,1.);
#684=CARTESIAN_POINT('',(11.7071067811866,5.29289321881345,-11.));
#685=LINE('',#684,#683);
#686=EDGE_CURVE('E418',#49,#656,#685,.T.);
#687=ORIENTED_EDGE('',*,*,#686,.T.);
#688=ORIENTED_EDGE('',*,*,#657,.T.);
#689=EDGE_LOOP('',(#680,#681,#687,#688));
#690=FACE_BOUND('',#689,.T.);
#691=ADVANCED_FACE('F305',(#690),#674,.T.);
#692=CARTESIAN_POINT('',(11.,4.5857864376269,-11.));
#693=DIRECTION('',(0.,0.,1.));
#694=DIRECTION('',(1.,0.,0.));
#695=AXIS2_PLACEMENT_3D('',#692,#693,#694);
#696=PLANE('',#695);
#697=ORIENTED_EDGE('',*,*,#50,.F.);
#698=ORIENTED_EDGE('',*,*,#108,.F.);
#699=ORIENTED_EDGE('',*,*,#141,.F.);
#700=ORIENTED_EDGE('',*,*,#172,.F.);
#701=ORIENTED_EDGE('',*,*,#205,.F.);
#702=ORIENTED_EDGE('',*,*,#236,.F.);
#703=ORIENTED_EDGE('',*,*,#269,.F.);
#704=ORIENTED_EDGE('',*,*,#300,.F.);
#705=ORIENTED_EDGE('',*,*,#333,.F.);
#706=ORIENTED_EDGE('',*,*,#364,.F.);
#707=ORIENTED_EDGE('',*,*,#397,.F.);
#708=ORIENTED_EDGE('',*,*,#439,.F.);
#709=ORIENTED_EDGE('',*,*,#472,.F.);
#710=ORIENTED_EDGE('',*,*,#503,.F.);
#711=ORIENTED_EDGE('',*,*,#536,.F.);
#712=ORIENTED_EDGE('',*,*,#567,.F.);
#713=ORIENTED_EDGE('',*,*,#600,.F.);
#714=ORIENTED_EDGE('',*,*,#631,.F.);
#715=ORIENTED_EDGE('',*,*,#664,.F.);
#716=ORIENTED_EDGE('',*,*,#686,.F.);
#717=EDGE_LOOP('',(#697,#698,#699,#700,#701,#702,#703,#704,#705,#706,#707,#708,#709,#710,#711,
#712,#713,#714,#715,#716));
#718=FACE_BOUND('',#717,.T.);
#719=ADVANCED_FACE('F201',(#718),#696,.F.);
#720=CARTESIAN_POINT('',(11.,4.5857864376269,5.));
#721=DIRECTION('',(0.,0.,1.));
#722=DIRECTION('',(1.,0.,0.));
#723=AXIS2_PLACEMENT_3D('',#720,#721,#722);
#724=PLANE('',#723);
#725=ORIENTED_EDGE('',*,*,#33,.T.);
#726=ORIENTED_EDGE('',*,*,#679,.T.);
#727=ORIENTED_EDGE('',*,*,#649,.T.);
#728=ORIENTED_EDGE('',*,*,#617,.T.);
#729=ORIENTED_EDGE('',*,*,#585,.T.);
#730=ORIENTED_EDGE('',*,*,#553,.T.);
#731=ORIENTED_EDGE('',*,*,#521,.T.);
#732=ORIENTED_EDGE('',*,*,#489,.T.);
#733=ORIENTED_EDGE('',*,*,#457,.T.);
#734=ORIENTED_EDGE('',*,*,#425,.T.);
#735=ORIENTED_EDGE('',*,*,#382,.T.);
#736=ORIENTED_EDGE('',*,*,#350,.T.);
#737=ORIENTED_EDGE('',*,*,#318,.T.);
#738=ORIENTED_EDGE('',*,*,#286,.T.);
#739=ORIENTED_EDGE('',*,*,#254,.T.);
#740=ORIENTED_EDGE('',*,*,#222,.T.);
#741=ORIENTED_EDGE('',*,*,#190,.T.);
#742=ORIENTED_EDGE('',*,*,#158,.T.);
#743=ORIENTED_EDGE('',*,*,#126,.T.);
#744=ORIENTED_EDGE('',*,*,#94,.T.);
#745=EDGE_LOOP('',(#725,#726,#727,#728,#729,#730,#731,#732,#733,#734,#735,#736,#737,#738,#739,
#740,#741,#742,#743,#744));
#746=FACE_BOUND('',#745,.T.);
#747=ADVANCED_FACE('F308',(#746),#724,.T.);
#748=CARTESIAN_POINT('',(12.,0.,-7.));
#749=DIRECTION('',(1.,0.,0.));
#750=DIRECTION('',(0.,0.,-1.));
#751=AXIS2_PLACEMENT_3D('',#748,#749,#750);
#752=CYLINDRICAL_SURFACE('',#751,2.25);
#753=CARTESIAN_POINT('',(10.75,0.,-7.));
#754=DIRECTION('',(1.,0.,0.));
#755=DIRECTION('',(0.,0.,-1.));
#756=AXIS2_PLACEMENT_3D('',#753,#754,#755);
#757=CIRCLE('',#756,2.25);
#758=CARTESIAN_POINT('',(10.75,0.,-9.25));
#759=VERTEX_POINT('',#758);
#760=EDGE_CURVE('E411',#759,#759,#757,.T.);
#761=ORIENTED_EDGE('',*,*,#760,.F.);
#762=EDGE_LOOP('',(#761));
#763=FACE_BOUND('',#762,.T.);
#764=ORIENTED_EDGE('',*,*,#84,.T.);
#765=EDGE_LOOP('',(#764));
#766=FACE_BOUND('',#765,.T.);
#767=ADVANCED_FACE('F391',(#763,#766),#752,.F.);
#768=CARTESIAN_POINT('',(10.75,0.,-7.));
#769=DIRECTION('',(-1.,0.,0.));
#770=DIRECTION('',(0.,0.,-1.));
#771=AXIS2_PLACEMENT_3D('',#768,#769,#770);
#772=SPHERICAL_SURFACE('',#771,2.25);
#773=ORIENTED_EDGE('',*,*,#760,.T.);
#774=EDGE_LOOP('',(#773));
#775=FACE_BOUND('',#774,.T.);
#776=ADVANCED_FACE('F395',(#775),#772,.T.);
#777=CARTESIAN_POINT('',(5.2,0.,0.));
#778=DIRECTION('',(-1.,0.,0.));
#779=DIRECTION('',(0.,0.,1.));
#780=AXIS2_PLACEMENT_3D('',#777,#778,#779);
#781=CYLINDRICAL_SURFACE('',#780,2.4585);
#782=ORIENTED_EDGE('',*,*,#73,.T.);
#783=EDGE_LOOP('',(#782));
#784=FACE_BOUND('',#783,.T.);
#785=ORIENTED_EDGE('',*,*,#415,.T.);
#786=EDGE_LOOP('',(#785));
#787=FACE_BOUND('',#786,.T.);
#788=ADVANCED_FACE('F399',(#784,#787),#781,.F.);
#789=CLOSED_SHELL('',(#60,#113,#146,#177,#210,#241,#274,#305,#338,#369,#402,#444,#477,#508,#541,
#572,#605,#636,#669,#691,#719,#747,#767,#776,#788));
#790=MANIFOLD_SOLID_BREP('B2',#789);
#791=CARTESIAN_POINT('',(-1.6,0.,0.));
#792=DIRECTION('',(1.,0.,0.));
#793=DIRECTION('',(0.,0.,-1.));
#794=AXIS2_PLACEMENT_3D('',#791,#792,#793);
#795=CYLINDRICAL_SURFACE('',#794,6.25);
#796=CARTESIAN_POINT('',(-1.6,0.,0.));
#797=DIRECTION('',(1.,0.,0.));
#798=DIRECTION('',(0.,0.,-1.));
#799=AXIS2_PLACEMENT_3D('',#796,#797,#798);
#800=CIRCLE('',#799,6.25);
#801=CARTESIAN_POINT('',(-1.6,0.,-6.25));
#802=VERTEX_POINT('',#801);
#803=EDGE_CURVE('E44',#802,#802,#800,.T.);
#804=ORIENTED_EDGE('',*,*,#803,.T.);
#805=EDGE_LOOP('',(#804));
#806=FACE_BOUND('',#805,.T.);
#807=CARTESIAN_POINT('',(0.,0.,0.));
#808=DIRECTION('',(1.,0.,0.));
#809=DIRECTION('',(0.,0.,-1.));
#810=AXIS2_PLACEMENT_3D('',#807,#808,#809);
#811=CIRCLE('',#810,6.25);
#812=CARTESIAN_POINT('',(0.,0.,-6.25));
#813=VERTEX_POINT('',#812);
#814=EDGE_CURVE('E662',#813,#813,#811,.T.);
#815=ORIENTED_EDGE('',*,*,#814,.F.);
#816=EDGE_LOOP('',(#815));
#817=FACE_BOUND('',#816,.T.);
#818=ADVANCED_FACE('F659',(#806,#817),#795,.T.);
#819=CARTESIAN_POINT('',(-1.6,0.,0.));
#820=DIRECTION('',(1.,0.,0.));
#821=DIRECTION('',(0.,0.,-1.));
#822=AXIS2_PLACEMENT_3D('',#819,#820,#821);
#823=PLANE('',#822);
#824=CARTESIAN_POINT('',(-1.6,0.,0.));
#825=DIRECTION('',(1.,0.,0.));
#826=DIRECTION('',(0.,0.,-1.));
#827=AXIS2_PLACEMENT_3D('',#824,#825,#826);
#828=CIRCLE('',#827,3.20000000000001);
#829=CARTESIAN_POINT('',(-1.6,0.,-3.20000000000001));
#830=VERTEX_POINT('',#829);
#831=EDGE_CURVE('E669',#830,#830,#828,.T.);
#832=ORIENTED_EDGE('',*,*,#831,.T.);
#833=EDGE_LOOP('',(#832));
#834=FACE_BOUND('',#833,.T.);
#835=ORIENTED_EDGE('',*,*,#803,.F.);
#836=EDGE_LOOP('',(#835));
#837=FACE_BOUND('',#836,.T.);
#838=ADVANCED_FACE('F677',(#834,#837),#823,.F.);
#839=CARTESIAN_POINT('',(0.,0.,0.));
#840=DIRECTION('',(1.,0.,0.));
#841=DIRECTION('',(0.,0.,-1.));
#842=AXIS2_PLACEMENT_3D('',#839,#840,#841);
#843=PLANE('',#842);
#844=CARTESIAN_POINT('',(0.,0.,0.));
#845=DIRECTION('',(1.,0.,0.));
#846=DIRECTION('',(0.,0.,-1.));
#847=AXIS2_PLACEMENT_3D('',#844,#845,#846);
#848=CIRCLE('',#847,3.20000000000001);
#849=CARTESIAN_POINT('',(0.,0.,-3.20000000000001));
#850=VERTEX_POINT('',#849);
#851=EDGE_CURVE('E671',#850,#850,#848,.T.);
#852=ORIENTED_EDGE('',*,*,#851,.F.);
#853=EDGE_LOOP('',(#852));
#854=FACE_BOUND('',#853,.T.);
#855=ORIENTED_EDGE('',*,*,#814,.T.);
#856=EDGE_LOOP('',(#855));
#857=FACE_BOUND('',#856,.T.);
#858=ADVANCED_FACE('F683',(#854,#857),#843,.T.);
#859=CARTESIAN_POINT('',(-1.6,0.,0.));
#860=DIRECTION('',(1.,0.,0.));
#861=DIRECTION('',(0.,0.,-1.));
#862=AXIS2_PLACEMENT_3D('',#859,#860,#861);
#863=CYLINDRICAL_SURFACE('',#862,3.20000000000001);
#864=ORIENTED_EDGE('',*,*,#831,.F.);
#865=EDGE_LOOP('',(#864));
#866=FACE_BOUND('',#865,.T.);
#867=ORIENTED_EDGE('',*,*,#851,.T.);
#868=EDGE_LOOP('',(#867));
#869=FACE_BOUND('',#868,.T.);
#870=ADVANCED_FACE('F680',(#866,#869),#863,.F.);
#871=CLOSED_SHELL('',(#818,#838,#858,#870));
#872=MANIFOLD_SOLID_BREP('B6',#871);
#873=CARTESIAN_POINT('',(10.4,0.,0.));
#874=DIRECTION('',(-1.,0.,0.));
#875=DIRECTION('',(0.,0.,1.));
#876=AXIS2_PLACEMENT_3D('',#873,#874,#875);
#877=PLANE('',#876);
#878=CARTESIAN_POINT('',(10.4,0.,0.));
#879=DIRECTION('',(-1.,0.,0.));
#880=DIRECTION('',(0.,0.,1.));
#881=AXIS2_PLACEMENT_3D('',#878,#879,#880);
#882=CIRCLE('',#881,3.);
#883=CARTESIAN_POINT('',(10.4,0.,3.));
#884=VERTEX_POINT('',#883);
#885=EDGE_CURVE('E857',#884,#884,#882,.T.);
#886=ORIENTED_EDGE('',*,*,#885,.F.);
#887=EDGE_LOOP('',(#886));
#888=FACE_BOUND('',#887,.T.);
#889=ADVANCED_FACE('F720',(#888),#877,.F.);
#890=CARTESIAN_POINT('',(-3.15662432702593,0.,0.));
#891=DIRECTION('',(-1.,0.,0.));
#892=DIRECTION('',(0.,0.,1.));
#893=AXIS2_PLACEMENT_3D('',#890,#891,#892);
#894=CYLINDRICAL_SURFACE('',#893,3.);
#895=CARTESIAN_POINT('',(-1.6,0.,0.));
#896=DIRECTION('',(-1.,0.,0.));
#897=DIRECTION('',(0.,0.,1.));
#898=AXIS2_PLACEMENT_3D('',#895,#896,#897);
#899=CIRCLE('',#898,3.);
#900=CARTESIAN_POINT('',(-1.6,0.,3.));
#901=VERTEX_POINT('',#900);
#902=EDGE_CURVE('E854',#901,#901,#899,.T.);
#903=ORIENTED_EDGE('',*,*,#902,.F.);
#904=EDGE_LOOP('',(#903));
#905=FACE_BOUND('',#904,.T.);
#906=ORIENTED_EDGE('',*,*,#885,.T.);
#907=EDGE_LOOP('',(#906));
#908=FACE_BOUND('',#907,.T.);
#909=ADVANCED_FACE('F920',(#905,#908),#894,.T.);
#910=CARTESIAN_POINT('',(-1.6,4.99999999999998,0.));
#911=DIRECTION('',(-1.,0.,0.));
#912=DIRECTION('',(0.,0.,1.));
#913=AXIS2_PLACEMENT_3D('',#910,#911,#912);
#914=PLANE('',#913);
#915=CARTESIAN_POINT('',(-1.6,0.,0.));
#916=DIRECTION('',(-1.,0.,0.));
#917=DIRECTION('',(0.,0.,1.));
#918=AXIS2_PLACEMENT_3D('',#915,#916,#917);
#919=CIRCLE('',#918,4.99999999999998);
#920=CARTESIAN_POINT('',(-1.6,0.,4.99999999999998));
#921=VERTEX_POINT('',#920);
#922=EDGE_CURVE('E851',#921,#921,#919,.T.);
#923=ORIENTED_EDGE('',*,*,#922,.F.);
#924=EDGE_LOOP('',(#923));
#925=FACE_BOUND('',#924,.T.);
#926=ORIENTED_EDGE('',*,*,#902,.T.);
#927=EDGE_LOOP('',(#926));
#928=FACE_BOUND('',#927,.T.);
#929=ADVANCED_FACE('F925',(#925,#928),#914,.F.);
#930=CARTESIAN_POINT('',(-3.15662432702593,0.,0.));
#931=DIRECTION('',(-1.,0.,0.));
#932=DIRECTION('',(0.,0.,1.));
#933=AXIS2_PLACEMENT_3D('',#930,#931,#932);
#934=CYLINDRICAL_SURFACE('',#933,4.99999999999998);
#935=CARTESIAN_POINT('',(-7.00000000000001,0.,0.));
#936=DIRECTION('',(-1.,0.,0.));
#937=DIRECTION('',(0.,0.,1.));
#938=AXIS2_PLACEMENT_3D('',#935,#936,#937);
#939=CIRCLE('',#938,4.99999999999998);
#940=CARTESIAN_POINT('',(-7.00000000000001,0.,4.99999999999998));
#941=VERTEX_POINT('',#940);
#942=EDGE_CURVE('E848',#941,#941,#939,.T.);
#943=ORIENTED_EDGE('',*,*,#942,.F.);
#944=EDGE_LOOP('',(#943));
#945=FACE_BOUND('',#944,.T.);
#946=ORIENTED_EDGE('',*,*,#922,.T.);
#947=EDGE_LOOP('',(#946));
#948=FACE_BOUND('',#947,.T.);
#949=ADVANCED_FACE('F932',(#945,#948),#934,.T.);
#950=CARTESIAN_POINT('',(-7.00000000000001,0.,0.));
#951=DIRECTION('',(1.,0.,0.));
#952=DIRECTION('',(0.,0.,-1.));
#953=AXIS2_PLACEMENT_3D('',#950,#951,#952);
#954=CONICAL_SURFACE('',#953,4.99999999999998,0.785398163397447);
#955=CARTESIAN_POINT('',(-7.6,0.,0.));
#956=DIRECTION('',(-1.,0.,0.));
#957=DIRECTION('',(0.,0.,1.));
#958=AXIS2_PLACEMENT_3D('',#955,#956,#957);
#959=CIRCLE('',#958,4.4);
#960=CARTESIAN_POINT('',(-7.6,0.,4.4));
#961=VERTEX_POINT('',#960);
#962=EDGE_CURVE('E834',#961,#961,#959,.T.);
#963=ORIENTED_EDGE('',*,*,#962,.F.);
#964=EDGE_LOOP('',(#963));
#965=FACE_BOUND('',#964,.T.);
#966=ORIENTED_EDGE('',*,*,#942,.T.);
#967=EDGE_LOOP('',(#966));
#968=FACE_BOUND('',#967,.T.);
#969=ADVANCED_FACE('F936',(#965,#968),#954,.T.);
#970=CARTESIAN_POINT('',(-7.6,4.4,0.));
#971=DIRECTION('',(1.,0.,0.));
#972=DIRECTION('',(0.,0.,-1.));
#973=AXIS2_PLACEMENT_3D('',#970,#971,#972);
#974=PLANE('',#973);
#975=DIRECTION('',(0.,0.5,0.866025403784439));
#976=VECTOR('',#975,1.);
#977=CARTESIAN_POINT('',(-7.6,3.2650635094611,0.655255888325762));
#978=LINE('',#977,#976);
#979=CARTESIAN_POINT('',(-7.6,1.44337567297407,-2.5));
#980=VERTEX_POINT('',#979);
#981=CARTESIAN_POINT('',(-7.6,2.88675134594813,0.));
#982=VERTEX_POINT('',#981);
#983=EDGE_CURVE('E742',#980,#982,#978,.T.);
#984=ORIENTED_EDGE('',*,*,#983,.T.);
#985=DIRECTION('',(0.,-0.5,0.866025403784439));
#986=VECTOR('',#985,1.);
#987=CARTESIAN_POINT('',(-7.6,3.2650635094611,-0.655255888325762));
#988=LINE('',#987,#986);
#989=CARTESIAN_POINT('',(-7.6,1.44337567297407,2.5));
#990=VERTEX_POINT('',#989);
#991=EDGE_CURVE('E657',#982,#990,#988,.T.);
#992=ORIENTED_EDGE('',*,*,#991,.T.);
#993=DIRECTION('',(0.,-1.,0.));
#994=VECTOR('',#993,1.);
#995=CARTESIAN_POINT('',(-7.6,4.4,2.5));
#996=LINE('',#995,#994);
#997=CARTESIAN_POINT('',(-7.6,-1.44337567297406,2.5));
#998=VERTEX_POINT('',#997);
#999=EDGE_CURVE('E728',#990,#998,#996,.T.);
#1000=ORIENTED_EDGE('',*,*,#999,.T.);
#1001=DIRECTION('',(0.,-0.5,-0.866025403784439));
#1002=VECTOR('',#1001,1.);
#1003=CARTESIAN_POINT('',(-7.6,-1.06506350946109,3.15525588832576));
#1004=LINE('',#1003,#1002);
#1005=CARTESIAN_POINT('',(-7.6,-2.88675134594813,0.));
#1006=VERTEX_POINT('',#1005);
#1007=EDGE_CURVE('E868',#998,#1006,#1004,.T.);
#1008=ORIENTED_EDGE('',*,*,#1007,.T.);
#1009=DIRECTION('',(0.,0.5,-0.866025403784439));
#1010=VECTOR('',#1009,1.);
#1011=CARTESIAN_POINT('',(-7.6,-1.06506350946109,-3.15525588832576));
#1012=LINE('',#1011,#1010);
#1013=CARTESIAN_POINT('',(-7.6,-1.44337567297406,-2.5));
#1014=VERTEX_POINT('',#1013);
#1015=EDGE_CURVE('E866',#1006,#1014,#1012,.T.);
#1016=ORIENTED_EDGE('',*,*,#1015,.T.);
#1017=DIRECTION('',(0.,1.,0.));
#1018=VECTOR('',#1017,1.);
#1019=CARTESIAN_POINT('',(-7.6,4.4,-2.5));
#1020=LINE('',#1019,#1018);
#1021=EDGE_CURVE('E864',#1014,#980,#1020,.T.);
#1022=ORIENTED_EDGE('',*,*,#1021,.T.);
#1023=EDGE_LOOP('',(#984,#992,#1000,#1008,#1016,#1022));
#1024=FACE_BOUND('',#1023,.T.);
#1025=ORIENTED_EDGE('',*,*,#962,.T.);
#1026=EDGE_LOOP('',(#1025));
#1027=FACE_BOUND('',#1026,.T.);
#1028=ADVANCED_FACE('F871',(#1024,#1027),#974,.F.);
#1029=CARTESIAN_POINT('',(-4.6,0.,0.));
#1030=DIRECTION('',(-1.,0.,0.));
#1031=DIRECTION('',(0.,0.,1.));
#1032=AXIS2_PLACEMENT_3D('',#1029,#1030,#1031);
#1033=PLANE('',#1032);
#1034=CARTESIAN_POINT('',(-4.6,0.,0.));
#1035=DIRECTION('',(-1.,0.,0.));
#1036=DIRECTION('',(0.,0.,1.));
#1037=AXIS2_PLACEMENT_3D('',#1034,#1035,#1036);
#1038=CIRCLE('',#1037,2.5);
#1039=CARTESIAN_POINT('',(-4.6,-2.16506350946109,1.25));
#1040=VERTEX_POINT('',#1039);
#1041=CARTESIAN_POINT('',(-4.6,0.,2.5));
#1042=VERTEX_POINT('',#1041);
#1043=EDGE_CURVE('E860',#1040,#1042,#1038,.T.);
#1044=ORIENTED_EDGE('',*,*,#1043,.F.);
#1045=DIRECTION('',(0.,0.5,0.866025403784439));
#1046=VECTOR('',#1045,1.);
#1047=CARTESIAN_POINT('',(-4.6,-2.88675134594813,0.));
#1048=LINE('',#1047,#1046);
#1049=CARTESIAN_POINT('',(-4.6,-1.44337567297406,2.5));
#1050=VERTEX_POINT('',#1049);
#1051=EDGE_CURVE('E825',#1040,#1050,#1048,.T.);
#1052=ORIENTED_EDGE('',*,*,#1051,.T.);
#1053=DIRECTION('',(0.,1.,0.));
#1054=VECTOR('',#1053,1.);
#1055=CARTESIAN_POINT('',(-4.6,-1.44337567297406,2.5));
#1056=LINE('',#1055,#1054);
#1057=EDGE_CURVE('E809',#1050,#1042,#1056,.T.);
#1058=ORIENTED_EDGE('',*,*,#1057,.T.);
#1059=EDGE_LOOP('',(#1044,#1052,#1058));
#1060=FACE_BOUND('',#1059,.T.);
#1061=ADVANCED_FACE('F887',(#1060),#1033,.T.);
#1062=CARTESIAN_POINT('',(-4.6,-2.16506350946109,-1.25));
#1063=VERTEX_POINT('',#1062);
#1064=EDGE_CURVE('E891',#1063,#1040,#1038,.T.);
#1065=ORIENTED_EDGE('',*,*,#1064,.F.);
#1066=DIRECTION('',(0.,-0.5,0.866025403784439));
#1067=VECTOR('',#1066,1.);
#1068=CARTESIAN_POINT('',(-4.6,-1.44337567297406,-2.5));
#1069=LINE('',#1068,#1067);
#1070=CARTESIAN_POINT('',(-4.6,-2.88675134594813,0.));
#1071=VERTEX_POINT('',#1070);
#1072=EDGE_CURVE('E821',#1063,#1071,#1069,.T.);
#1073=ORIENTED_EDGE('',*,*,#1072,.T.);
#1074=EDGE_CURVE('E826',#1071,#1040,#1048,.T.);
#1075=ORIENTED_EDGE('',*,*,#1074,.T.);
#1076=EDGE_LOOP('',(#1065,#1073,#1075));
#1077=FACE_BOUND('',#1076,.T.);
#1078=ADVANCED_FACE('F910',(#1077),#1033,.T.);
#1079=CARTESIAN_POINT('',(-4.6,0.,-2.5));
#1080=VERTEX_POINT('',#1079);
#1081=EDGE_CURVE('E892',#1080,#1063,#1038,.T.);
#1082=ORIENTED_EDGE('',*,*,#1081,.F.);
#1083=DIRECTION('',(0.,-1.,0.));
#1084=VECTOR('',#1083,1.);
#1085=CARTESIAN_POINT('',(-4.6,1.44337567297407,-2.5));
#1086=LINE('',#1085,#1084);
#1087=CARTESIAN_POINT('',(-4.6,-1.44337567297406,-2.5));
#1088=VERTEX_POINT('',#1087);
#1089=EDGE_CURVE('E815',#1080,#1088,#1086,.T.);
#1090=ORIENTED_EDGE('',*,*,#1089,.T.);
#1091=EDGE_CURVE('E822',#1088,#1063,#1069,.T.);
#1092=ORIENTED_EDGE('',*,*,#1091,.T.);
#1093=EDGE_LOOP('',(#1082,#1090,#1092));
#1094=FACE_BOUND('',#1093,.T.);
#1095=ADVANCED_FACE('F905',(#1094),#1033,.T.);
#1096=CARTESIAN_POINT('',(-4.6,2.1650635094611,-1.25));
#1097=VERTEX_POINT('',#1096);
#1098=EDGE_CURVE('E893',#1097,#1080,#1038,.T.);
#1099=ORIENTED_EDGE('',*,*,#1098,.F.);
#1100=DIRECTION('',(0.,-0.5,-0.866025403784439));
#1101=VECTOR('',#1100,1.);
#1102=CARTESIAN_POINT('',(-4.6,2.88675134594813,0.));
#1103=LINE('',#1102,#1101);
#1104=CARTESIAN_POINT('',(-4.6,1.44337567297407,-2.5));
#1105=VERTEX_POINT('',#1104);
#1106=EDGE_CURVE('E814',#1097,#1105,#1103,.T.);
#1107=ORIENTED_EDGE('',*,*,#1106,.T.);
#1108=EDGE_CURVE('E817',#1105,#1080,#1086,.T.);
#1109=ORIENTED_EDGE('',*,*,#1108,.T.);
#1110=EDGE_LOOP('',(#1099,#1107,#1109));
#1111=FACE_BOUND('',#1110,.T.);
#1112=ADVANCED_FACE('F896',(#1111),#1033,.T.);
#1113=CARTESIAN_POINT('',(-4.6,2.1650635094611,1.25));
#1114=VERTEX_POINT('',#1113);
#1115=EDGE_CURVE('E799',#1114,#1097,#1038,.T.);
#1116=ORIENTED_EDGE('',*,*,#1115,.F.);
#1117=DIRECTION('',(0.,0.5,-0.866025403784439));
#1118=VECTOR('',#1117,1.);
#1119=CARTESIAN_POINT('',(-4.6,1.44337567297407,2.5));
#1120=LINE('',#1119,#1118);
#1121=CARTESIAN_POINT('',(-4.6,2.88675134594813,0.));
#1122=VERTEX_POINT('',#1121);
#1123=EDGE_CURVE('E793',#1114,#1122,#1120,.T.);
#1124=ORIENTED_EDGE('',*,*,#1123,.T.);
#1125=EDGE_CURVE('E797',#1122,#1097,#1103,.T.);
#1126=ORIENTED_EDGE('',*,*,#1125,.T.);
#1127=EDGE_LOOP('',(#1116,#1124,#1126));
#1128=FACE_BOUND('',#1127,.T.);
#1129=ADVANCED_FACE('F795',(#1128),#1033,.T.);
#1130=EDGE_CURVE('E861',#1042,#1114,#1038,.T.);
#1131=ORIENTED_EDGE('',*,*,#1130,.F.);
#1132=CARTESIAN_POINT('',(-4.6,1.44337567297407,2.5));
#1133=VERTEX_POINT('',#1132);
#1134=EDGE_CURVE('E829',#1042,#1133,#1056,.T.);
#1135=ORIENTED_EDGE('',*,*,#1134,.T.);
#1136=EDGE_CURVE('E735',#1133,#1114,#1120,.T.);
#1137=ORIENTED_EDGE('',*,*,#1136,.T.);
#1138=EDGE_LOOP('',(#1131,#1135,#1137));
#1139=FACE_BOUND('',#1138,.T.);
#1140=ADVANCED_FACE('F917',(#1139),#1033,.T.);
#1141=CARTESIAN_POINT('',(-4.6,1.44337567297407,2.5));
#1142=DIRECTION('',(0.,0.866025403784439,0.5));
#1143=DIRECTION('',(0.,-0.5,0.866025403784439));
#1144=AXIS2_PLACEMENT_3D('',#1141,#1142,#1143);
#1145=PLANE('',#1144);
#1146=ORIENTED_EDGE('',*,*,#991,.F.);
#1147=DIRECTION('',(-1.,0.,0.));
#1148=VECTOR('',#1147,1.);
#1149=CARTESIAN_POINT('',(-4.6,2.88675134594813,0.));
#1150=LINE('',#1149,#1148);
#1151=EDGE_CURVE('E804',#1122,#982,#1150,.T.);
#1152=ORIENTED_EDGE('',*,*,#1151,.F.);
#1153=ORIENTED_EDGE('',*,*,#1123,.F.);
#1154=ORIENTED_EDGE('',*,*,#1136,.F.);
#1155=DIRECTION('',(-1.,0.,0.));
#1156=VECTOR('',#1155,1.);
#1157=CARTESIAN_POINT('',(-4.6,1.44337567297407,2.5));
#1158=LINE('',#1157,#1156);
#1159=EDGE_CURVE('E832',#1133,#990,#1158,.T.);
#1160=ORIENTED_EDGE('',*,*,#1159,.T.);
#1161=EDGE_LOOP('',(#1146,#1152,#1153,#1154,#1160));
#1162=FACE_BOUND('',#1161,.T.);
#1163=ADVANCED_FACE('F805',(#1162),#1145,.F.);
#1164=CARTESIAN_POINT('',(-4.6,-1.44337567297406,2.5));
#1165=DIRECTION('',(0.,0.,1.));
#1166=DIRECTION('',(0.,-1.,0.));
#1167=AXIS2_PLACEMENT_3D('',#1164,#1165,#1166);
#1168=PLANE('',#1167);
#1169=ORIENTED_EDGE('',*,*,#999,.F.);
#1170=ORIENTED_EDGE('',*,*,#1159,.F.);
#1171=ORIENTED_EDGE('',*,*,#1134,.F.);
#1172=ORIENTED_EDGE('',*,*,#1057,.F.);
#1173=DIRECTION('',(-1.,0.,0.));
#1174=VECTOR('',#1173,1.);
#1175=CARTESIAN_POINT('',(-4.6,-1.44337567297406,2.5));
#1176=LINE('',#1175,#1174);
#1177=EDGE_CURVE('E835',#1050,#998,#1176,.T.);
#1178=ORIENTED_EDGE('',*,*,#1177,.T.);
#1179=EDGE_LOOP('',(#1169,#1170,#1171,#1172,#1178));
#1180=FACE_BOUND('',#1179,.T.);
#1181=ADVANCED_FACE('F883',(#1180),#1168,.F.);
#1182=CARTESIAN_POINT('',(-4.6,-2.88675134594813,0.));
#1183=DIRECTION('',(0.,-0.866025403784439,0.5));
#1184=DIRECTION('',(0.,-0.5,-0.866025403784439));
#1185=AXIS2_PLACEMENT_3D('',#1182,#1183,#1184);
#1186=PLANE('',#1185);
#1187=ORIENTED_EDGE('',*,*,#1007,.F.);
#1188=ORIENTED_EDGE('',*,*,#1177,.F.);
#1189=ORIENTED_EDGE('',*,*,#1051,.F.);
#1190=ORIENTED_EDGE('',*,*,#1074,.F.);
#1191=DIRECTION('',(-1.,0.,0.));
#1192=VECTOR('',#1191,1.);
#1193=CARTESIAN_POINT('',(-4.6,-2.88675134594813,0.));
#1194=LINE('',#1193,#1192);
#1195=EDGE_CURVE('E838',#1071,#1006,#1194,.T.);
#1196=ORIENTED_EDGE('',*,*,#1195,.T.);
#1197=EDGE_LOOP('',(#1187,#1188,#1189,#1190,#1196));
#1198=FACE_BOUND('',#1197,.T.);
#1199=ADVANCED_FACE('F878',(#1198),#1186,.F.);
#1200=CARTESIAN_POINT('',(-4.6,-1.44337567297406,-2.5));
#1201=DIRECTION('',(0.,-0.866025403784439,-0.5));
#1202=DIRECTION('',(0.,0.5,-0.866025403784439));
#1203=AXIS2_PLACEMENT_3D('',#1200,#1201,#1202);
#1204=PLANE('',#1203);
#1205=ORIENTED_EDGE('',*,*,#1015,.F.);
#1206=ORIENTED_EDGE('',*,*,#1195,.F.);
#1207=ORIENTED_EDGE('',*,*,#1072,.F.);
#1208=ORIENTED_EDGE('',*,*,#1091,.F.);
#1209=DIRECTION('',(-1.,0.,0.));
#1210=VECTOR('',#1209,1.);
#1211=CARTESIAN_POINT('',(-4.6,-1.44337567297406,-2.5));
#1212=LINE('',#1211,#1210);
#1213=EDGE_CURVE('E841',#1088,#1014,#1212,.T.);
#1214=ORIENTED_EDGE('',*,*,#1213,.T.);
#1215=EDGE_LOOP('',(#1205,#1206,#1207,#1208,#1214));
#1216=FACE_BOUND('',#1215,.T.);
#1217=ADVANCED_FACE('F908',(#1216),#1204,.F.);
#1218=CARTESIAN_POINT('',(-4.6,1.44337567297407,-2.5));
#1219=DIRECTION('',(0.,0.,-1.));
#1220=DIRECTION('',(0.,1.,0.));
#1221=AXIS2_PLACEMENT_3D('',#1218,#1219,#1220);
#1222=PLANE('',#1221);
#1223=ORIENTED_EDGE('',*,*,#1021,.F.);
#1224=ORIENTED_EDGE('',*,*,#1213,.F.);
#1225=ORIENTED_EDGE('',*,*,#1089,.F.);
#1226=ORIENTED_EDGE('',*,*,#1108,.F.);
#1227=DIRECTION('',(-1.,0.,0.));
#1228=VECTOR('',#1227,1.);
#1229=CARTESIAN_POINT('',(-4.6,1.44337567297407,-2.5));
#1230=LINE('',#1229,#1228);
#1231=EDGE_CURVE('E808',#1105,#980,#1230,.T.);
#1232=ORIENTED_EDGE('',*,*,#1231,.T.);
#1233=EDGE_LOOP('',(#1223,#1224,#1225,#1226,#1232));
#1234=FACE_BOUND('',#1233,.T.);
#1235=ADVANCED_FACE('F901',(#1234),#1222,.F.);
#1236=CARTESIAN_POINT('',(-4.6,2.88675134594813,0.));
#1237=DIRECTION('',(0.,0.866025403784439,-0.5));
#1238=DIRECTION('',(0.,0.5,0.866025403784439));
#1239=AXIS2_PLACEMENT_3D('',#1236,#1237,#1238);
#1240=PLANE('',#1239);
#1241=ORIENTED_EDGE('',*,*,#983,.F.);
#1242=ORIENTED_EDGE('',*,*,#1231,.F.);
#1243=ORIENTED_EDGE('',*,*,#1106,.F.);
#1244=ORIENTED_EDGE('',*,*,#1125,.F.);
#1245=ORIENTED_EDGE('',*,*,#1151,.T.);
#1246=EDGE_LOOP('',(#1241,#1242,#1243,#1244,#1245));
#1247=FACE_BOUND('',#1246,.T.);
#1248=ADVANCED_FACE('F812',(#1247),#1240,.F.);
#1249=CARTESIAN_POINT('',(-4.6,0.,0.));
#1250=DIRECTION('',(-1.,0.,0.));
#1251=DIRECTION('',(0.,0.,1.));
#1252=AXIS2_PLACEMENT_3D('',#1249,#1250,#1251);
#1253=CONICAL_SURFACE('',#1252,2.5,1.0471975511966);
#1254=CARTESIAN_POINT('',(-3.15662432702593,0.,0.));
#1255=VERTEX_POINT('',#1254);
#1256=VERTEX_LOOP('',#1255);
#1257=FACE_BOUND('',#1256,.T.);
#1258=ORIENTED_EDGE('',*,*,#1130,.T.);
#1259=ORIENTED_EDGE('',*,*,#1115,.T.);
#1260=ORIENTED_EDGE('',*,*,#1098,.T.);
#1261=ORIENTED_EDGE('',*,*,#1081,.T.);
#1262=ORIENTED_EDGE('',*,*,#1064,.T.);
#1263=ORIENTED_EDGE('',*,*,#1043,.T.);
#1264=EDGE_LOOP('',(#1258,#1259,#1260,#1261,#1262,#1263));
#1265=FACE_BOUND('',#1264,.T.);
#1266=ADVANCED_FACE('F722',(#1257,#1265),#1253,.F.);
#1267=CLOSED_SHELL('',(#889,#909,#929,#949,#969,#1028,#1061,#1078,#1095,#1112,#1129,#1140,#1163,
#1181,#1199,#1217,#1235,#1248,#1266));
#1268=MANIFOLD_SOLID_BREP('B39',#1267);
#1269=ADVANCED_BREP_SHAPE_REPRESENTATION('',(#18,#790,#872,#1268),#14);
#1270=SHAPE_DEFINITION_REPRESENTATION(#9,#1269);
ENDSEC;
END-ISO-10303-21;
